! (c) 2009  Infineon Technologies AG, Munich
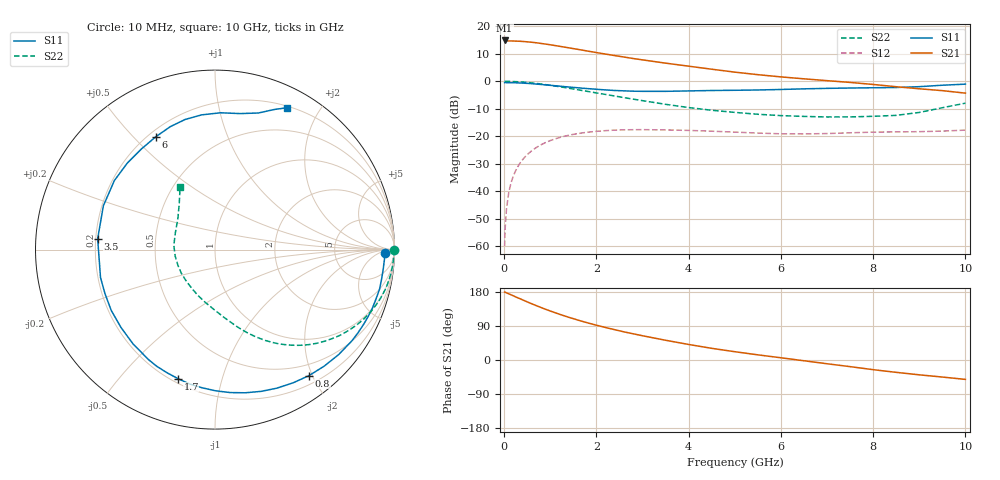
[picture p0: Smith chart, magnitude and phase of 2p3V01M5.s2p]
! Infineon Technologies  Discrete & RF Semiconductors
! BFP420
! VCE =  3.0 V,  IC =  1.5 mA
! Common Emitter S-Parameters:  Nov 2009
# GHz  S  MA  R  50
!  f  S11  S21  S12  S22
! GHz  MAG  ANG  MAG  ANG  MAG  ANG  MAG  ANG
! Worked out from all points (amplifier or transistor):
!   46 points, 10 MHz to 10 GHz, reference 50 ohm
!   highest |S21| = 14.9 dB at 10 MHz (marker M1)
!   |S21| within 3 dB of that: start of sweep to 1.512 GHz
!   unconditionally stable (mu >= 1): 4.143 GHz to end of sweep
!   at 300 MHz: K = 0.03, MSG = 22.8 dB, |S12| = -31.0 dB
!   at 1.7 GHz: K = 0.31, MSG = 15.1 dB, |S12| = -18.8 dB
!   at 10 GHz: K = 1.27, MAG = 3.6 dB, |S12| = -17.8 dB
!   lowest NFmin = 0.52 dB at 900 MHz
!   S11 on the Smith chart (normalised r, x): 10 MHz: 31, -13; 800 MHz: 0.32, -1.95; 1.7 GHz: 0.22, -0.73; 3.5 GHz: 0.21, +0.04; 6 GHz: 0.23, +0.58; 10 GHz: 0.22, +1.61
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0.01  0.9463 -1.3  5.534 179.3  0.001 87.2  0.9959 0.0
0.02  0.9472 -1.3  5.361 179.2  0.002 84.2  0.9961 -0.7
0.05  0.9458 -3.2  5.391 177.2  0.0047 88.4  0.9965 -1.8
0.1  0.9435 -6.8  5.423 174.7  0.0095 85.8  0.9953 -3.7
0.2  0.9429 -13.5  5.413 169.4  0.019 82.2  0.9897 -7.4
0.35  0.9312 -23.7  5.344 161.4  0.033 76.2  0.9748 -13.0
0.5  0.9165 -33.7  5.225 153.4  0.0463 70.5  0.9524 -18.3
0.8  0.8759 -53.3  4.882 138.5  0.07 59.2  0.8923 -28.3
1  0.8453 -66.0  4.618 129.3  0.0834 52.3  0.8449 -34.4
1.2  0.8153 -78.1  4.336 120.7  0.0948 46.0  0.7959 -39.9
1.4  0.7869 -89.7  4.064 112.7  0.1042 40.0  0.7476 -45.0
1.7  0.7476 -106.1  3.686 101.8  0.1152 32.1  0.6782 -51.7
2.2  0.6963 -130.9  3.127 85.7  0.1265 20.8  0.5761 -61.3
2.6  0.6701 -149.6  2.762 74.2  0.1309 12.9  0.5044 -68.1
3  0.6566 -166.3  2.453 64.0  0.1319 6.3  0.4444 -74.3
3.5  0.6565 174.7  2.139 52.1  0.1304 -0.5  0.3811 -82.4
4.5  0.6799 145.6  1.659 30.8  0.1236 -10.0  0.2971 -101.1
5.5  0.6947 126.1  1.32 13.6  0.1142 -14.8  0.2513 -121.1
6  0.7099 117.7  1.202 5.9  0.1108 -15.2  0.2375 -132.5
7  0.7437 103.0  1.027 -9.9  0.112 -14.9  0.2244 -156.7
8.5  0.7707 79.5  0.796 -32.6  0.12 -19.2  0.2399 157.0
10  0.8872 63.0  0.609 -51.2  0.1293 -21.5  0.3999 119.1
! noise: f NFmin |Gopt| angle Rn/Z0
0.9  0.52  0.55  33  0.27
1.8  1.07  0.35  77  0.21
2.4  1.18  0.36  101  0.18
3  1.41  0.36  134  0.13
4  1.68  0.4  -172  0.1
5  2.08  0.44  -130  0.32
6  2.89  0.57  -114  0.39
